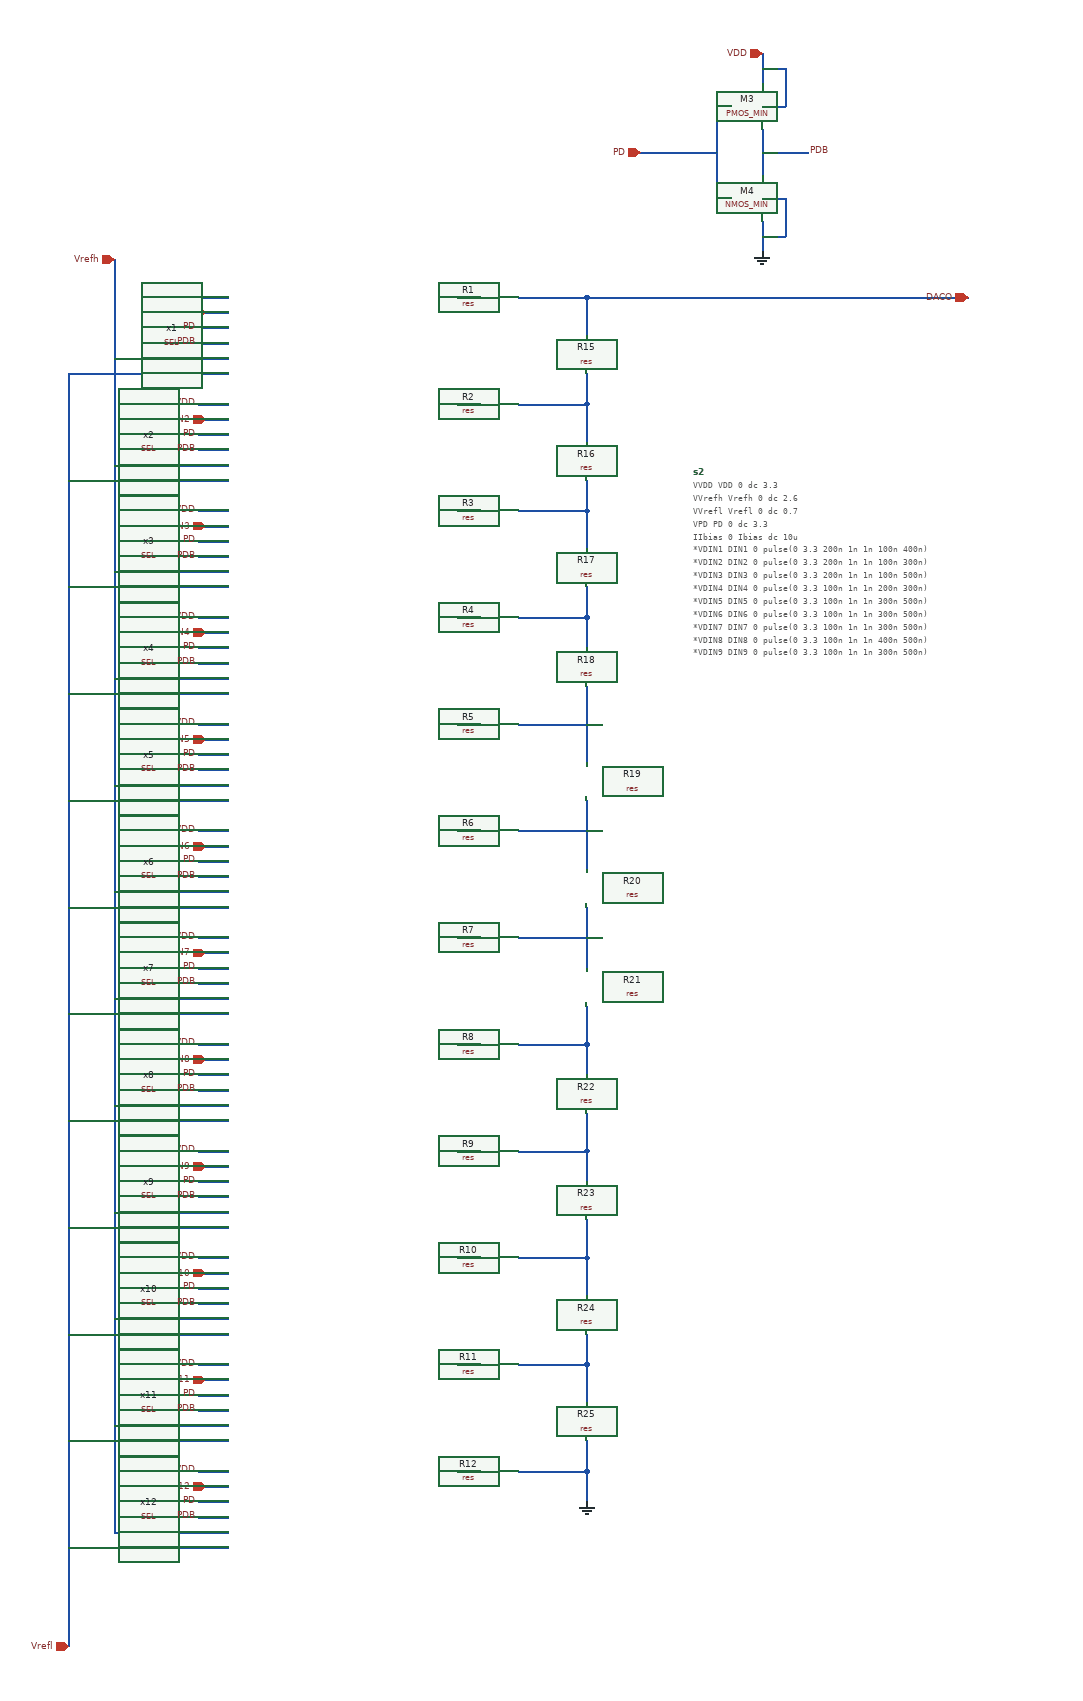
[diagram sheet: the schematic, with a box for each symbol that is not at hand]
v {xschem version=3.4.8RC file_version=1.3}
G {}
K {}
V {}
S {}
F {}
E {}
N -520 -780 -430 -780 {lab=DACO}
N -520 -640 -430 -640 {lab=#net1}
N -600 -780 -570 -780 {lab=#net2}
N -600 -640 -570 -640 {lab=#net3}
N -600 -500 -570 -500 {lab=#net4}
N -600 -220 -570 -220 {lab=#net5}
N -600 -360 -570 -360 {lab=#net6}
N -600 -80 -570 -80 {lab=#net7}
N -600 60 -570 60 {lab=#net8}
N -600 200 -570 200 {lab=#net9}
N -600 340 -570 340 {lab=#net10}
N -600 480 -570 480 {lab=#net11}
N -600 620 -570 620 {lab=#net12}
N -600 760 -570 760 {lab=#net13}
N -1050 -740 -1050 540 {lab=Vrefh}
N -1050 420 -910 420 {lab=Vrefh}
N -1050 -420 -910 -420 {lab=Vrefh}
N -1110 440 -910 440 {lab=Vrefl}
N -1110 -400 -910 -400 {lab=Vrefl}
N -430 -780 -290 -780 {lab=DACO}
N -930 -760 -900 -760 {lab=DIN1}
N -930 -620 -900 -620 {lab=DIN2}
N -930 -480 -900 -480 {lab=DIN3}
N -930 -340 -900 -340 {lab=DIN4}
N -930 -200 -900 -200 {lab=DIN5}
N -930 -60 -900 -60 {lab=DIN6}
N -930 80 -900 80 {lab=DIN7}
N -930 220 -900 220 {lab=DIN8}
N -930 360 -900 360 {lab=DIN9}
N -930 500 -900 500 {lab=DIN10}
N -930 640 -900 640 {lab=DIN11}
N -930 780 -900 780 {lab=DIN12}
N -430 -780 -430 -750 {lab=DACO}
N -520 -500 -430 -500 {lab=#net14}
N -520 -360 -430 -360 {lab=#net15}
N -520 -220 -430 -220 {lab=#net16}
N -430 -240 -430 -210 {lab=#net16}
N -520 -80 -430 -80 {lab=#net17}
N -520 60 -430 60 {lab=#net18}
N -430 -210 -430 -170 {lab=#net16}
N -430 -120 -430 -90 {lab=#net17}
N -430 -90 -430 -60 {lab=#net17}
N -430 30 -430 70 {lab=#net18}
N -520 200 -430 200 {lab=#net19}
N -520 480 -440 480 {lab=#net20}
N -520 620 -440 620 {lab=#net21}
N -440 620 -430 620 {lab=#net21}
N -520 760 -430 760 {lab=GND}
N -430 620 -430 660 {lab=#net21}
N -430 730 -430 760 {lab=GND}
N -430 760 -430 800 {lab=GND}
N -200 -880 -200 -840 {lab=GND}
N -200 -910 -170 -910 {lab=GND}
N -170 -910 -170 -860 {lab=GND}
N -200 -860 -170 -860 {lab=GND}
N -200 -1000 -200 -940 {lab=PDB}
N -200 -970 -160 -970 {lab=PDB}
N -260 -1030 -240 -1030 {lab=PD}
N -260 -1030 -260 -910 {lab=PD}
N -260 -910 -240 -910 {lab=PD}
N -360 -970 -260 -970 {lab=PD}
N -200 -1100 -200 -1060 {lab=VDD}
N -200 -1080 -170 -1080 {lab=VDD}
N -170 -1080 -170 -1030 {lab=VDD}
N -200 -1030 -170 -1030 {lab=VDD}
N -940 -780 -900 -780 {lab=VDD}
N -1050 -830 -1050 -740 {lab=Vrefh}
N -940 760 -900 760 {lab=VDD}
N -940 620 -900 620 {lab=VDD}
N -940 480 -900 480 {lab=VDD}
N -940 340 -900 340 {lab=VDD}
N -940 200 -900 200 {lab=VDD}
N -940 60 -900 60 {lab=VDD}
N -940 -80 -900 -80 {lab=VDD}
N -940 -220 -900 -220 {lab=VDD}
N -940 -360 -900 -360 {lab=VDD}
N -940 -500 -900 -500 {lab=VDD}
N -940 -640 -900 -640 {lab=VDD}
N -1110 -570 -1110 650 {lab=Vrefl}
N -290 -780 -210 -780 {lab=DACO}
N -160 -970 -140 -970 {lab=PDB}
N -210 -780 -140 -780 {lab=DACO}
N -1110 690 -1110 760 {lab=Vrefl}
N -1110 650 -1110 690 {lab=Vrefl}
N -940 -740 -900 -740 {lab=PD}
N -940 -720 -900 -720 {lab=PDB}
N -1050 -700 -900 -700 {lab=Vrefh}
N -1110 -680 -900 -680 {lab=Vrefl}
N -1110 -680 -1110 -570 {lab=Vrefl}
N -940 -600 -900 -600 {lab=PD}
N -940 -580 -900 -580 {lab=PDB}
N -1050 -560 -900 -560 {lab=Vrefh}
N -1110 -540 -900 -540 {lab=Vrefl}
N -940 -460 -900 -460 {lab=PD}
N -940 -440 -900 -440 {lab=PDB}
N -910 -420 -900 -420 {lab=Vrefh}
N -910 -400 -900 -400 {lab=Vrefl}
N -940 -320 -900 -320 {lab=PD}
N -940 -300 -900 -300 {lab=PDB}
N -1050 -280 -900 -280 {lab=Vrefh}
N -1110 -260 -900 -260 {lab=Vrefl}
N -940 -180 -900 -180 {lab=PD}
N -940 -160 -900 -160 {lab=PDB}
N -1050 -140 -900 -140 {lab=Vrefh}
N -1110 -120 -900 -120 {lab=Vrefl}
N -940 -40 -900 -40 {lab=PD}
N -940 -20 -900 -20 {lab=PDB}
N -940 100 -900 100 {lab=PD}
N -940 120 -900 120 {lab=PDB}
N -940 240 -900 240 {lab=PD}
N -940 260 -900 260 {lab=PDB}
N -910 420 -900 420 {lab=Vrefh}
N -910 440 -900 440 {lab=Vrefl}
N -1110 760 -1110 950 {lab=Vrefl}
N -1050 540 -1050 840 {lab=Vrefh}
N -1050 840 -900 840 {lab=Vrefh}
N -1110 860 -900 860 {lab=Vrefl}
N -1110 720 -900 720 {lab=Vrefl}
N -1050 700 -900 700 {lab=Vrefh}
N -1110 580 -900 580 {lab=Vrefl}
N -1050 560 -900 560 {lab=Vrefh}
N -1110 300 -900 300 {lab=Vrefl}
N -1050 280 -900 280 {lab=Vrefh}
N -1110 160 -900 160 {lab=Vrefl}
N -1050 140 -900 140 {lab=Vrefh}
N -1110 20 -900 20 {lab=Vrefl}
N -1050 0 -900 0 {lab=Vrefh}
N -940 380 -900 380 {lab=PD}
N -940 400 -900 400 {lab=PDB}
N -940 520 -900 520 {lab=PD}
N -940 540 -900 540 {lab=PDB}
N -940 660 -900 660 {lab=PD}
N -940 680 -900 680 {lab=PDB}
N -940 800 -900 800 {lab=PD}
N -940 820 -900 820 {lab=PDB}
N -430 660 -430 670 {lab=#net21}
N -430 720 -430 730 {lab=GND}
N -430 -750 -430 -730 {lab=DACO}
N -430 -680 -430 -640 {lab=#net1}
N -430 580 -430 620 {lab=#net21}
N -440 480 -430 480 {lab=#net20}
N -430 480 -430 530 {lab=#net20}
N -520 340 -430 340 {lab=#net22}
N -430 340 -430 380 {lab=#net22}
N -430 430 -430 480 {lab=#net20}
N -430 290 -430 340 {lab=#net22}
N -430 200 -430 240 {lab=#net19}
N -430 150 -430 200 {lab=#net19}
N -430 70 -430 100 {lab=#net18}
N -430 20 -430 30 {lab=#net18}
N -430 -60 -430 -30 {lab=#net17}
N -430 -270 -430 -240 {lab=#net16}
N -430 -360 -430 -320 {lab=#net15}
N -430 -500 -430 -450 {lab=#net14}
N -430 -400 -430 -360 {lab=#net15}
N -430 -640 -430 -590 {lab=#net1}
N -430 -540 -430 -500 {lab=#net14}
N -1110 950 -1110 990 {lab=Vrefl}
N -140 -780 30 -780 {lab=DACO}
N 30 -780 70 -780 {lab=DACO}
C {res.sym} -510 -790 1 0 {name=R1
value=200k
footprint=1206
device=resistor
m=1}
C {res.sym} -440 -740 0 0 {name=R15
value=100k
footprint=1206
device=resistor
m=1}
C {ipin.sym} -1050 -830 1 0 {name=p1 lab=Vrefh}
C {ipin.sym} -1110 990 3 0 {name=p2 lab=Vrefl}
C {ipin.sym} -930 -760 0 0 {name=p4 lab=DIN1}
C {ipin.sym} -930 -620 0 0 {name=p6 lab=DIN2}
C {ipin.sym} -930 -480 0 0 {name=p7 lab=DIN3}
C {ipin.sym} -930 -340 0 0 {name=p8 lab=DIN4}
C {ipin.sym} -930 -200 0 0 {name=p9 lab=DIN5}
C {ipin.sym} -930 -60 0 0 {name=p10 lab=DIN6}
C {ipin.sym} -930 80 0 0 {name=p11 lab=DIN7}
C {ipin.sym} -930 220 0 0 {name=p12 lab=DIN8}
C {ipin.sym} -930 360 0 0 {name=p13 lab=DIN9}
C {ipin.sym} -930 500 0 0 {name=p14 lab=DIN10}
C {ipin.sym} -930 640 0 0 {name=p15 lab=DIN11}
C {ipin.sym} -930 780 0 0 {name=p16 lab=DIN12}
C {code_shown.sym} -290 -550 0 0 {name=s2 only_toplevel=false value=
"
VVDD VDD 0 dc 3.3
VVrefh Vrefh 0 dc 2.6
VVrefl Vrefl 0 dc 0.7
VPD PD 0 dc 3.3
IIbias 0 Ibias dc 10u

*VDIN1 DIN1 0 pulse(0 3.3 200n 1n 1n 100n 400n)
*VDIN2 DIN2 0 pulse(0 3.3 200n 1n 1n 100n 300n)
*VDIN3 DIN3 0 pulse(0 3.3 200n 1n 1n 100n 500n)
*VDIN4 DIN4 0 pulse(0 3.3 100n 1n 1n 200n 300n)
*VDIN5 DIN5 0 pulse(0 3.3 100n 1n 1n 300n 500n)
*VDIN6 DIN6 0 pulse(0 3.3 100n 1n 1n 300n 500n)
*VDIN7 DIN7 0 pulse(0 3.3 100n 1n 1n 300n 500n)
*VDIN8 DIN8 0 pulse(0 3.3 100n 1n 1n 400n 500n)
*VDIN9 DIN9 0 pulse(0 3.3 100n 1n 1n 300n 500n)
*VDIN10 DIN10 0 pulse(0 3.3 100n 1n 1n 300n 500n)
*VDIN11 DIN11 0 pulse(0 3.3 100n 1n 1n 300n 500n)
*VDIN12 DIN12 0 pulse(0 3.3 100n 1n 1n 400n 500n)

*DNL-INL
VDIN1 DIN1 0 pulse(3.3 0 100n 1n 1n 204800n 409600n)
VDIN2 DIN2 0 pulse(3.3 0 100n 1n 1n 102400n 204800n)
VDIN3 DIN3 0 pulse(3.3 0 100n 1n 1n 51200n 102400n)
VDIN4 DIN4 0 pulse(3.3 0 100n 1n 1n 25600n 51200n)
VDIN5 DIN5 0 pulse(3.3 0 100n 1n 1n 12800n 25600n)
VDIN6 DIN6 0 pulse(3.3 0 100n 1n 1n 6400n 12800n)
VDIN7 DIN7 0 pulse(3.3 0 100n 1n 1n 3200n 6400n)
VDIN8 DIN8 0 pulse(3.3 0 100n 1n 1n 1600n 3200n)
VDIN9 DIN9 0 pulse(3.3 0 100n 1n 1n 800n 1600n)
VDIN10 DIN10 0 pulse(3.3 0 100n 1n 1n 400n 800n)
VDIN11 DIN11 0 pulse(3.3 0 100n 1n 1n 200n 400n)
VDIN12 DIN12 0 pulse(3.3 0 100n 1n 1n 100n 200n)


*.meas tran IDDA AVG I(V1) from=200n to=300n
*.meas tran IDDM MAX I(V1) from=200n to=300n
*.meas tran IDDMI MIN I(V1) from=200n to=300n 
*.meas tran IAVG AVG I(V2) from=200n to=300n
*.meas tran IDDS MAX I(V2) from=200n to=300n
*.meas tran 12h000 FIND V(OUT) AT=90n
*.meas tran 12h1ff FIND V(DACO) AT=190n
*.meas tran 12hfff FIND V(OUT) AT=290n
*.meas tran 12h0ff FIND V(DACO) AT=390n
*.meas tran 12h111 FIND V(DACO) AT=490n
*.meas tran IAVG2 AVG I(V2) from=100.1n to=200n
*.meas tran gain1 AVG V(DACO)
*.meas tran gain2 AVG V(OUT)

.include /home/raidonn/LRCircuit/spicemodel/ocs65_stl_n3_typ.para
.include /home/raidonn/LRCircuit/spicemodel/ocs65_stl_p3_typ.para

.control
save all
set filetype=ascii
set wr_singlescale
set wr_vecnames
option numdgt=5
tran 100n 410u 90n
*tran 1n 500n
plot V(DACO)
*plot I(V1)
*plot I(V2)

linearize V(DACO)

write "RDAC_only.raw"
wrdata "RDAC_INL_DNL3.csv" V(DACO)

.endc"
}
C {res.sym} -510 -650 1 0 {name=R2
value=200k
footprint=1206
device=resistor
m=1}
C {res.sym} -510 -510 1 0 {name=R3
value=200k
footprint=1206
device=resistor
m=1}
C {res.sym} -510 -370 1 0 {name=R4
value=200k
footprint=1206
device=resistor
m=1}
C {res.sym} -510 -230 1 0 {name=R5
value=200k
footprint=1206
device=resistor
m=1}
C {res.sym} -510 -90 1 0 {name=R6
value=200k
footprint=1206
device=resistor
m=1}
C {res.sym} -510 50 1 0 {name=R7
value=200k
footprint=1206
device=resistor
m=1}
C {res.sym} -510 190 1 0 {name=R8
value=200k
footprint=1206
device=resistor
m=1}
C {res.sym} -510 330 1 0 {name=R9
value=200k
footprint=1206
device=resistor
m=1}
C {res.sym} -510 470 1 0 {name=R10
value=200k
footprint=1206
device=resistor
m=1}
C {res.sym} -510 610 1 0 {name=R11
value=200k
footprint=1206
device=resistor
m=1}
C {res.sym} -510 750 1 0 {name=R12
value=200k
footprint=1206
device=resistor
m=1}
C {res.sym} -440 -600 0 0 {name=R16
value=100k
footprint=1206
device=resistor
m=1}
C {res.sym} -440 -460 0 0 {name=R17
value=100k
footprint=1206
device=resistor
m=1}
C {res.sym} -440 -330 0 0 {name=R18
value=100k
footprint=1206
device=resistor
m=1}
C {res.sym} -440 -180 0 0 {name=R19
value=100k
footprint=1206
device=resistor
m=1}
C {res.sym} -440 -40 0 0 {name=R20
value=100k
footprint=1206
device=resistor
m=1}
C {res.sym} -440 90 0 0 {name=R21
value=100k
footprint=1206
device=resistor
m=1}
C {res.sym} -440 230 0 0 {name=R22
value=100k
footprint=1206
device=resistor
m=1}
C {res.sym} -440 370 0 0 {name=R23
value=100k
footprint=1206
device=resistor
m=1}
C {res.sym} -440 520 0 0 {name=R24
value=100k
footprint=1206
device=resistor
m=1}
C {res.sym} -440 660 0 0 {name=R25
value=100k
footprint=1206
device=resistor
m=1}
C {gnd.sym} -430 800 0 0 {name=l1 lab=GND}
C {PMOS_MIN.sym} -240 -1030 0 0 {name=M3 model=p3.0 w=3.5u l=0.35u as=0 ps=0 ad=0 pd=0 m=1}
C {NMOS_MIN.sym} -240 -910 0 0 {name=M4 model=n3.0 w=3.5u l=0.35u as=0 ps=0 ad=0 pd=0 m=1}
C {ipin.sym} -360 -970 0 0 {name=p5 lab=PD}
C {gnd.sym} -200 -840 0 0 {name=l2 lab=GND}
C {ipin.sym} -200 -1100 1 0 {name=p19 lab=VDD}
C {lab_pin.sym} -940 -780 0 0 {name=l5 sig_type=std_logic lab=VDD}
C {lab_pin.sym} -940 760 0 0 {name=l8 sig_type=std_logic lab=VDD}
C {lab_pin.sym} -940 620 0 0 {name=l9 sig_type=std_logic lab=VDD}
C {lab_pin.sym} -940 480 0 0 {name=l10 sig_type=std_logic lab=VDD}
C {lab_pin.sym} -940 340 0 0 {name=l11 sig_type=std_logic lab=VDD}
C {lab_pin.sym} -940 200 0 0 {name=l12 sig_type=std_logic lab=VDD}
C {lab_pin.sym} -940 60 0 0 {name=l13 sig_type=std_logic lab=VDD}
C {lab_pin.sym} -940 -80 0 0 {name=l14 sig_type=std_logic lab=VDD}
C {lab_pin.sym} -940 -220 0 0 {name=l15 sig_type=std_logic lab=VDD}
C {lab_pin.sym} -940 -360 0 0 {name=l16 sig_type=std_logic lab=VDD}
C {lab_pin.sym} -940 -500 0 0 {name=l17 sig_type=std_logic lab=VDD}
C {lab_pin.sym} -940 -640 0 0 {name=l18 sig_type=std_logic lab=VDD}
C {lab_pin.sym} -140 -970 2 0 {name=l24 sig_type=std_logic lab=PDB}
C {/home/raidonn/LRCircuit/work4/origin/SEL.sym} -750 -730 0 0 {name=x1}
C {/home/raidonn/LRCircuit/work4/origin/SEL.sym} -750 -590 0 0 {name=x2}
C {/home/raidonn/LRCircuit/work4/origin/SEL.sym} -750 -450 0 0 {name=x3}
C {/home/raidonn/LRCircuit/work4/origin/SEL.sym} -750 -310 0 0 {name=x4}
C {/home/raidonn/LRCircuit/work4/origin/SEL.sym} -750 -170 0 0 {name=x5}
C {/home/raidonn/LRCircuit/work4/origin/SEL.sym} -750 -30 0 0 {name=x6}
C {/home/raidonn/LRCircuit/work4/origin/SEL.sym} -750 110 0 0 {name=x7}
C {/home/raidonn/LRCircuit/work4/origin/SEL.sym} -750 250 0 0 {name=x8}
C {/home/raidonn/LRCircuit/work4/origin/SEL.sym} -750 390 0 0 {name=x9}
C {/home/raidonn/LRCircuit/work4/origin/SEL.sym} -750 530 0 0 {name=x10}
C {/home/raidonn/LRCircuit/work4/origin/SEL.sym} -750 670 0 0 {name=x11}
C {/home/raidonn/LRCircuit/work4/origin/SEL.sym} -750 810 0 0 {name=x12}
C {lab_pin.sym} -940 -740 0 0 {name=l3 sig_type=std_logic lab=PD}
C {lab_pin.sym} -940 -720 0 0 {name=l6 sig_type=std_logic lab=PDB}
C {lab_pin.sym} -940 -600 0 0 {name=l7 sig_type=std_logic lab=PD}
C {lab_pin.sym} -940 -580 0 0 {name=l22 sig_type=std_logic lab=PDB}
C {lab_pin.sym} -940 -460 0 0 {name=l23 sig_type=std_logic lab=PD}
C {lab_pin.sym} -940 -440 0 0 {name=l25 sig_type=std_logic lab=PDB}
C {lab_pin.sym} -940 -320 0 0 {name=l26 sig_type=std_logic lab=PD}
C {lab_pin.sym} -940 -300 0 0 {name=l27 sig_type=std_logic lab=PDB}
C {lab_pin.sym} -940 -180 0 0 {name=l28 sig_type=std_logic lab=PD}
C {lab_pin.sym} -940 -160 0 0 {name=l29 sig_type=std_logic lab=PDB}
C {lab_pin.sym} -940 -40 0 0 {name=l30 sig_type=std_logic lab=PD}
C {lab_pin.sym} -940 -20 0 0 {name=l31 sig_type=std_logic lab=PDB}
C {lab_pin.sym} -940 100 0 0 {name=l32 sig_type=std_logic lab=PD}
C {lab_pin.sym} -940 120 0 0 {name=l33 sig_type=std_logic lab=PDB}
C {lab_pin.sym} -940 240 0 0 {name=l34 sig_type=std_logic lab=PD}
C {lab_pin.sym} -940 260 0 0 {name=l35 sig_type=std_logic lab=PDB}
C {lab_pin.sym} -940 380 0 0 {name=l36 sig_type=std_logic lab=PD}
C {lab_pin.sym} -940 400 0 0 {name=l37 sig_type=std_logic lab=PDB}
C {lab_pin.sym} -940 520 0 0 {name=l38 sig_type=std_logic lab=PD}
C {lab_pin.sym} -940 540 0 0 {name=l39 sig_type=std_logic lab=PDB}
C {lab_pin.sym} -940 660 0 0 {name=l40 sig_type=std_logic lab=PD}
C {lab_pin.sym} -940 680 0 0 {name=l41 sig_type=std_logic lab=PDB}
C {lab_pin.sym} -940 800 0 0 {name=l42 sig_type=std_logic lab=PD}
C {lab_pin.sym} -940 820 0 0 {name=l43 sig_type=std_logic lab=PDB}
C {iopin.sym} 70 -780 0 0 {name=p17 lab=DACO}
